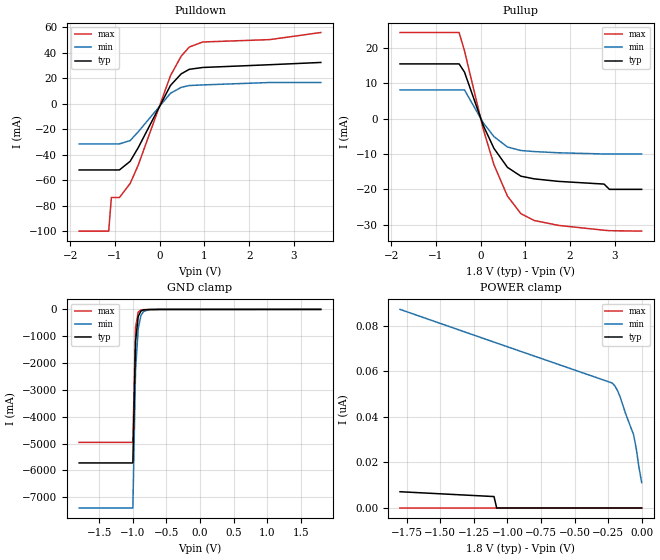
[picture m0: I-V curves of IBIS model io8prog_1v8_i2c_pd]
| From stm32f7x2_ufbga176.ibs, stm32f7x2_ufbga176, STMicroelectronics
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|   Model io8prog_1v8_i2c_pd
[Model]  io8prog_1v8_i2c_pd
Model_type I/O
Polarity   Non-Inverting
Enable   Active-Low
Vinl =   0.540000V
Vinh =   1.260000V
Vmeas =  0.900000V
Cref =   100.000000nF
Rref =   1.000000k
Vref =   1.800000V
C_comp   2.500900pF   2.333900pF   2.735800pF
[Temperature Range]   25.000000   0.125000k   -40.000000
[Pullup Reference]   1.800000V   1.600000V   2.000000V
[Pulldown Reference]   0.0V   0.0V   0.0V
[POWER Clamp Reference]   1.800000V   1.600000V   2.000000V
[GND Clamp Reference]   0.0V   0.0V   0.0V
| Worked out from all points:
|   slope of the pulldown table from 0 to 0.27 V, typ, clamps not added: 17.2 ohm
|   slope of the pullup table from 0 to 0.27 V, typ, clamps not added: 34.9 ohm
|   GND clamp passes 1 mA (typ) near -0.57 V on its own axis
[Pulldown]
|Voltage   I(typ)   I(min)   I(max)
-1.8V     -51.99mA   -31.53mA   -100mA
-1.14V    -51.99mA   -31.53mA   -100mA
-1.08V    -51.99mA   -31.53mA   -73.62mA
-900mV    -51.99mA   -31.53mA   -73.62mA
-660mV    -45.19mA   -28.93mA   -62.58mA
-480mV    -34.51mA   -22.06mA   -48.23mA
240mV     14.31mA    8.182mA    21.95mA
480mV     23.44mA    12.84mA    37.31mA
660mV     26.99mA    14.27mA    44.47mA
960mV     28.44mA    14.75mA    48.45mA
2.46V     30.61mA    16.66mA    50.32mA
3.6V      32.39mA    16.66mA    55.89mA
[Pullup]
|Voltage   I(typ)   I(min)   I(max)
-1.8V     15.46mA    8.103mA    24.33mA
-480mV    15.46mA    8.103mA    24.33mA
-360mV    13.15mA    8.103mA    19.18mA
60mV      -1.95mA    -1.198mA   -2.977mA
300mV     -8.441mA   -5.092mA   -13.07mA
600mV     -13.77mA   -8.025mA   -21.88mA
900mV     -16.27mA   -9.02mA    -26.86mA
1.2V      -17.03mA   -9.318mA   -28.8mA
1.74V     -17.74mA   -9.658mA   -30.18mA
2.76V     -18.51mA   -10mA      -31.55mA
2.88V     -20mA      -10mA      -31.68mA
3.6V      -20mA      -10mA      -31.8mA
[GND_clamp]
|Voltage   I(typ)   I(min)   I(max)
-1.8V     -5.722A    -7.401A    -4.956A
-1V       -5.722A    -7.401A    -4.956A
-960mV    -1.203A    -2.294A    -680.3mA
-920mV    -260.8mA   -717.4mA   -103.7mA
-880mV    -62.28mA   -228.9mA   -23.86mA
-840mV    -19.06mA   -76.33mA   -11.32mA
-760mV    -5.585mA   -11.67mA   -6.214mA
-640mV    -2.06mA    -2.422mA   -2.211mA
1.8V      44.31uA    33.68uA    51.4uA
[POWER_clamp]
|Voltage   I(typ)   I(min)   I(max)
-1.8V     7.131nA    87.08nA    0A
-1.1V     5.014nA    72.73nA    0A
-1.08V    0A         72.32nA    0A
-220mV    0A         54.8nA     0A
-200mV    0A         53.55nA    0A
-180mV    0A         51.5nA     0A
-160mV    0A         48.61nA    0A
-120mV    0A         41.45nA    0A
-60mV     0A         32.08nA    0A
-40mV     0A         25.93nA    0A
-20mV     0A         17.79nA    0A
0V        0A         11.13nA    0A
[Ramp]
| variable   typ   min   max
dV/dt_r  0.49514/6.00000u   0.27767/6.00000u   0.74652/6.00000u
dV/dt_f  0.75185/6.00000u   0.44015/6.00000u   0.96649/6.00000u
R_load = 50.000000
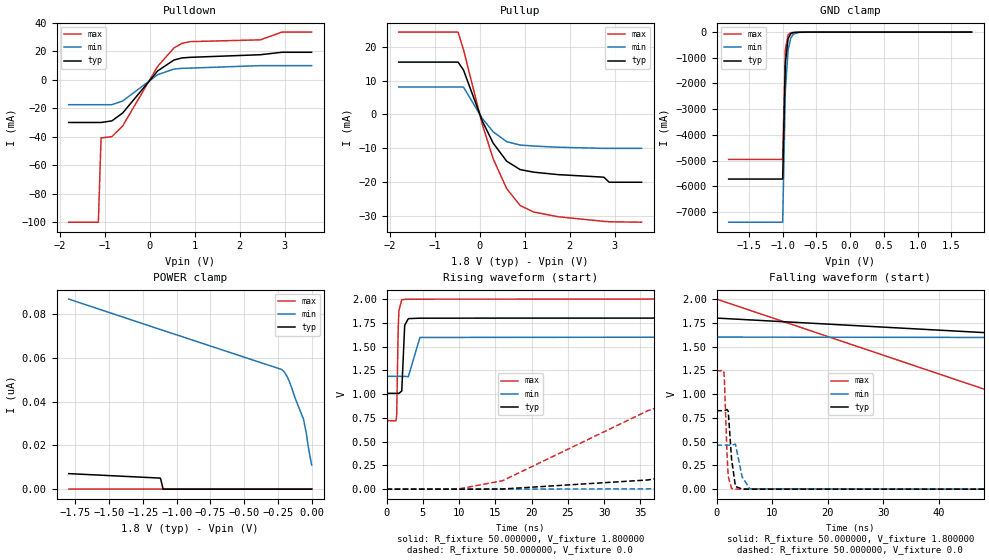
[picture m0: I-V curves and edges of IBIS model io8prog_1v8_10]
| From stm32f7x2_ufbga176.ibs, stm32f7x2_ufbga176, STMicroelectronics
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|   Model io8prog_1v8_10
[Model]  io8prog_1v8_10
Model_type I/O
Polarity   Non-Inverting
Enable   Active-Low
Vinl =   0.540000V
Vinh =   1.260000V
Vmeas =  0.900000V
Cref =   100.000000nF
Rref =   1.000000k
Vref =   1.800000V
C_comp   2.595400pF   2.437600pF   2.808600pF
[Temperature Range]   25.000000   0.125000k   -40.000000
[Pullup Reference]   1.800000V   1.600000V   2.000000V
[Pulldown Reference]   0.0V   0.0V   0.0V
[POWER Clamp Reference]   1.800000V   1.600000V   2.000000V
[GND Clamp Reference]   0.0V   0.0V   0.0V
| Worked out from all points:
|   slope of the pulldown table from 0 to 0.27 V, typ, clamps not added: 31 ohm
|   slope of the pullup table from 0 to 0.27 V, typ, clamps not added: 34.9 ohm
|   GND clamp passes 1 mA (typ) near -0.57 V on its own axis
|   rising waveform, R_fixture 50.000000, V_fixture 1.800000: 20-80 % time 213ps typ, 327ps min, 178ps max; typ from 1.01 V to 1.8 V
|   rising waveform, R_fixture 50.000000, V_fixture 0.0: 20-80 % time 42.7ns typ, 83.8ns min, 21ns max; typ from 0 V to 0.826 V
|   falling waveform, R_fixture 50.000000, V_fixture 1.800000: 20-80 % time 46.7ns typ, 84ns min, 43.8ns max; typ from 1.8 V to 1.01 V
|   falling waveform, R_fixture 50.000000, V_fixture 0.0: 20-80 % time 641ps typ, 956ps min, 471ps max; typ from 0.826 V to 0 V
[Pulldown]
|Voltage   I(typ)   I(min)   I(max)
-1.8V     -30mA      -17.52mA   -100mA
-1.14V    -30mA      -17.52mA   -100mA
-1.08V    -30mA      -17.52mA   -40.9mA
-840mV    -28.88mA   -17.52mA   -39.94mA
-600mV    -23.35mA   -14.94mA   -32.45mA
180mV     6.236mA    3.598mA    9.492mA
540mV     13.85mA    7.499mA    22.29mA
720mV     15.32mA    8.029mA    25.55mA
900mV     15.74mA    8.167mA    26.76mA
2.46V     17.56mA    9.912mA    28.02mA
2.94V     19.29mA    9.912mA    33.46mA
3.6V      19.29mA    9.912mA    33.46mA
[Pullup]
|Voltage   I(typ)   I(min)   I(max)
-1.8V     15.46mA    8.103mA    24.33mA
-480mV    15.46mA    8.103mA    24.33mA
-360mV    13.15mA    8.103mA    19.18mA
60mV      -1.95mA    -1.198mA   -2.977mA
300mV     -8.441mA   -5.092mA   -13.07mA
600mV     -13.78mA   -8.025mA   -21.88mA
900mV     -16.27mA   -9.02mA    -26.86mA
1.2V      -17.03mA   -9.318mA   -28.8mA
1.74V     -17.75mA   -9.658mA   -30.18mA
2.76V     -18.51mA   -10mA      -31.55mA
2.88V     -20mA      -10mA      -31.68mA
3.6V      -20mA      -10mA      -31.8mA
[GND_clamp]
|Voltage   I(typ)   I(min)   I(max)
-1.8V     -5.722A    -7.401A    -4.956A
-1V       -5.722A    -7.401A    -4.956A
-960mV    -1.203A    -2.294A    -680.3mA
-920mV    -260.8mA   -717.4mA   -103.7mA
-880mV    -62.26mA   -228.9mA   -23.84mA
-840mV    -19.05mA   -76.32mA   -11.31mA
-760mV    -5.573mA   -11.66mA   -6.2mA
-640mV    -2.048mA   -2.413mA   -2.197mA
1.8V      0A         0A         0A
[POWER_clamp]
|Voltage   I(typ)   I(min)   I(max)
-1.8V     7.116nA    87.04nA    0A
-1.12V    5.066nA    73.1nA     0A
-1.1V     0A         72.68nA    0A
-220mV    0A         54.75nA    0A
-200mV    0A         53.5nA     0A
-180mV    0A         51.44nA    0A
-160mV    0A         48.56nA    0A
-120mV    0A         41.39nA    0A
-60mV     0A         32.03nA    0A
-40mV     0A         25.87nA    0A
-20mV     0A         17.74nA    0A
0V        0A         11.07nA    0A
[Ramp]
| variable   typ   min   max
dV/dt_r  0.49566/42.66378n   0.27796/83.67398n   0.74712/20.99695n
dV/dt_f  0.47520/41.50240n   0.24780/72.61905n   0.76706/23.28960n
R_load = 50.000000
[Rising Waveform]
R_fixture= 50.000000
V_fixture= 1.800000
V_fixture_min= 1.600000
V_fixture_max= 2.000000
|time   V(typ)   V(min)   V(max)
0s        1.008V     1.187V     721.6mV
1.301ns   1.008V     1.187V     719.1mV
1.401ns   1.008V     1.187V     779.7mV
1.602ns   1.008V     1.187V     1.664V
1.702ns   1.006V     1.187V     1.879V
2.102ns   1.034V     1.187V     1.992V
2.503ns   1.724V     1.187V     1.997V
3.003ns   1.794V     1.183V     1.998V
4.605ns   1.799V     1.596V     1.999V
49.85ns   1.8V       1.6V       2V
[Rising Waveform]
R_fixture= 50.000000
V_fixture= 0.0
V_fixture_min= 0.0
V_fixture_max= 0.0
|time   V(typ)   V(min)   V(max)
0s        3.541nV    238.4nV    1.408nV
10.01ns   -100.7uV   -45.08uV   3.671mV
16.02ns   1.898mV    -32.52uV   89.43mV
36.04ns   96.74mV    3.52mV     826.4mV
46.05ns   223.2mV    10.06mV    1.07V
74.07ns   578.8mV    62.76mV    1.228V
116.1ns   783.6mV    224.6mV    1.244V
170.2ns   822mV      378mV      1.245V
228.2ns   825.6mV    438mV      1.245V
997ns     826.1mV    463.3mV    1.245V
[Falling Waveform]
R_fixture= 50.000000
V_fixture= 1.800000
V_fixture_min= 1.600000
V_fixture_max= 2.000000
|time   V(typ)   V(min)   V(max)
0s        1.8V       1.6V       2V
50.05ns   1.641V     1.596V     1.014V
100.1ns   1.13V      1.45V      741.6mV
150.2ns   1.033V     1.282V     723.9mV
200.2ns   1.014V     1.226V     722mV
250.2ns   1.01V      1.202V     721.6mV
400.4ns   1.008V     1.188V     721.6mV
4.955us   1.008V     1.187V     721.6mV
[Falling Waveform]
R_fixture= 50.000000
V_fixture= 0.0
V_fixture_min= 0.0
V_fixture_max= 0.0
|time   V(typ)   V(min)   V(max)
0s        826.1mV    463.3mV    1.245V
1.301ns   825.5mV    463.3mV    1.248V
1.401ns   825.2mV    463.3mV    1.169V
1.902ns   837.7mV    463.2mV    347.8mV
2.102ns   820.2mV    462.9mV    133.5mV
2.703ns   315.7mV    462.9mV    7.385mV
3.403ns   28.59mV    473.6mV    960.4uV
4.605ns   811.9uV    128mV      378.7uV
6.006ns   189.2uV    3.65mV     207.4uV
49.85ns   3.541nV    238.4nV    1.408nV
